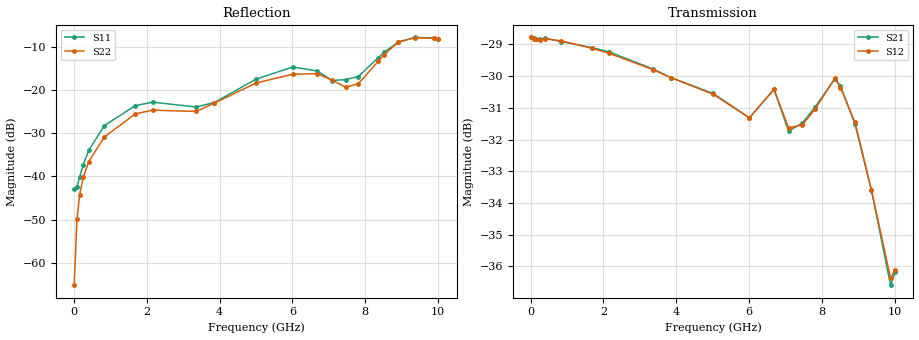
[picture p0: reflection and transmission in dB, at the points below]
! Device ID: PE43705
! Serial: 1
! Insertion: A
! Impedance: 50 ohm
! Temp: 25C
! VDD: 3.400V
! Attenuation Step: 27.75dB
#  Hz  S  RI  R  50
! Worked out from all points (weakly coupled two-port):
!   401 points, 10 MHz to 10.01 GHz, reference 50 ohm
!   highest |S21| = -28.79 dB at 10 MHz (marker M1); lowest = -36.6 dB at 9.885 GHz (marker M2)
!   lowest |S11| = -43.0 dB at 10 MHz (marker M3), VSWR 1.01, Z = 49.3 + j0.0499 ohm
!   |S11| at or under -10 dB: start of sweep to 8.69 GHz
!   |S22| runs from -65.2 to -7.8 dB; largest |S21 - S12| = 0.00067
!   S11 on the Smith chart (normalised r, x): 10 MHz: 0.99, +0.00; 7.46 GHz: 0.82, +0.16; 8.51 GHz: 0.82, +0.48; 9.36 GHz: 0.54, +0.48; 10.01 GHz: 0.48, +0.26
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1e7  -0.00705 0.000506  0.0364 -0.000101  0.0364 -9.18e-05  -0.000253 0.000487
8.5e7  -0.00669 0.00355  0.0363 -0.000832  0.0362 -0.000841  0.000301 0.00315
1.6e8  -0.0071 0.00682  0.0362 -0.0015  0.0362 -0.00146  6.65e-05 0.00613
2.6e8  -0.00822 0.011  0.0361 -0.00244  0.036 -0.00238  -0.00101 0.00976
4.1e8  -0.0112 0.0166  0.0361 -0.00357  0.036 -0.00372  -0.00371 0.0144
8.35e8  -0.0283 0.0264  0.0351 -0.00733  0.0352 -0.00734  -0.0185 0.0218
1.685e9  -0.0641 0.0164  0.0322 -0.0139  0.0321 -0.0139  -0.0517 0.0119
2.16e9  -0.0725 0.00284  0.03 -0.0171  0.0298 -0.0171  -0.0586 0.00094
3.36e9  -0.0637 0.00325  0.0227 -0.0232  0.0227 -0.0231  -0.0564 0.00507
3.86e9  -0.067 0.0261  0.0197 -0.0245  0.0197 -0.0245  -0.0678 0.0203
5.01e9  -0.1036 0.0861  0.0138 -0.0263  0.014 -0.0261  -0.1055 0.06
6.01e9  -0.1561 0.1001  0.00823 -0.0259  0.00824 -0.0259  -0.1326 0.0761
6.685e9  -0.1469 0.0793  0.00611 -0.0295  0.0058 -0.0296  -0.1382 0.0709
7.085e9  -0.1138 0.0615  0.000406 -0.0259  0.000432 -0.0262  -0.1078 0.0742
7.46e9  -0.093 0.0943  0.00182 -0.0266  0.00202 -0.0264  -0.0717 0.0813
7.81e9  -0.0489 0.1354  0.00169 -0.0282  0.00163 -0.028  -0.0462 0.1091
8.36e9  -0.0167 0.2381  -0.00676 -0.0306  -0.00654 -0.0307  -0.0334 0.2144
8.51e9  -0.0254 0.2722  -0.00977 -0.0289  -0.00944 -0.0288  -0.0424 0.2527
8.91e9  -0.0805 0.3518  -0.0131 -0.0231  -0.0131 -0.0233  -0.1034 0.3459
9.36e9  -0.1809 0.3669  -0.012 -0.0171  -0.0122 -0.017  -0.1964 0.3535
9.885e9  -0.2969 0.27  -0.0045 -0.0141  -0.0048 -0.0144  -0.3228 0.2358
1.001e10  -0.3144 0.2284  -0.00254 -0.0153  -0.00272 -0.0154  -0.3445 0.1853
